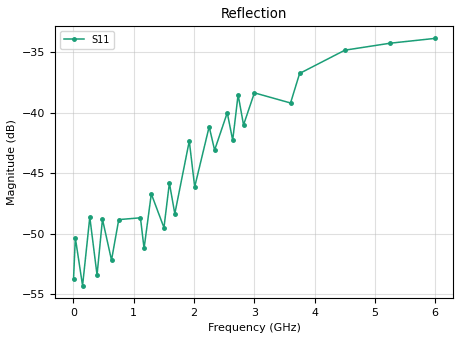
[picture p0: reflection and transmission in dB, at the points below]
! NMT Kit SMA(f) typ SOLT V1 - Load s1p data
! Ref Plane 0 mm
#  MHz  S  RI  R  50
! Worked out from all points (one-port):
!   201 points, 1 MHz to 6.001 GHz, reference 50 ohm
!   lowest |S11| = -54.3 dB at 151 MHz (marker M1), VSWR 1.00, Z = 49.9 + j0.137 ohm
!   |S11| at or under -10 dB: start of sweep to end of sweep
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1  0.00199 0.00049
31  0.000173 0.00303
151  -0.00135 0.00137
271  -0.00365 -0.000593
391  -0.0021 0.000355
481  -0.00361 -0.000298
631  -0.00242 -0.0004
751  -0.00361 -7.4e-05
1111  -0.00356 -0.000908
1171  -0.00272 -0.000354
1291  -0.00437 -0.00148
1501  -0.00334 -0.000163
1591  -0.00495 -0.00132
1681  -0.00378 -0.000533
1921  -0.00661 -0.00383
2011  -0.0039 -0.00302
2251  -0.00739 -0.0047
2341  -0.00612 -0.0034
2551  -0.00788 -0.00616
2641  -0.00616 -0.00461
2731  -0.00971 -0.00683
2821  -0.00695 -0.00557
3001  -0.0105 -0.00599
3601  -0.00983 -0.00488
3751  -0.0134 -0.00565
4501  -0.0178 -0.00356
5251  -0.0194 0.000271
6001  -0.0198 0.00457
